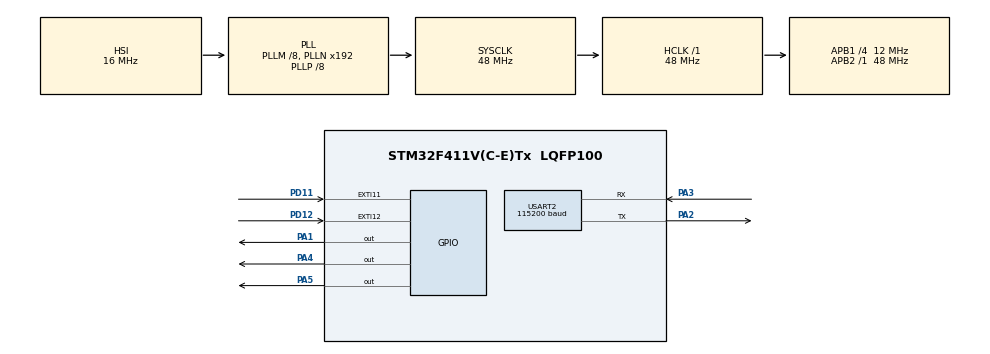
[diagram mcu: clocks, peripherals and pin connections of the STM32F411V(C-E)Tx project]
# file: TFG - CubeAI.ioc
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Mcu.Family=STM32F4
Mcu.Name=STM32F411V(C-E)Tx
Mcu.Package=LQFP100
NVIC.EXTI15_10_IRQn=true\:7\:0\:false\:false\:true\:true\:true\:false
NVIC.PriorityGroup=NVIC_PRIORITYGROUP_0
NVIC.TIM1_UP_TIM10_IRQn=true\:5\:0\:false\:false\:true\:true\:true\:false
NVIC.USART2_IRQn=true\:6\:0\:false\:false\:true\:true\:true\:false
PA1.Signal=GPIO_Output
PA2.Mode=Asynchronous
PA2.Signal=USART2_TX
PA3.Mode=Asynchronous
PA3.Signal=USART2_RX
PA4.Signal=GPIO_Output
PA5.Signal=GPIO_Output
PD11.Signal=GPXTI11
PD12.Signal=GPXTI12
ProjectManager.HeapSize=0x200
ProjectManager.StackSize=0x400
ProjectManager.TargetToolchain=STM32CubeIDE
RCC.48MHZClocksFreq_Value=48000000
RCC.AHBFreq_Value=48000000
RCC.APB1CLKDivider=RCC_HCLK_DIV4
RCC.APB1Freq_Value=12000000
RCC.APB1TimFreq_Value=24000000
RCC.APB2Freq_Value=48000000
RCC.APB2TimFreq_Value=48000000
RCC.CortexFreq_Value=48000000
RCC.HCLKFreq_Value=48000000
RCC.HSE_VALUE=8000000
RCC.HSI_VALUE=16000000
RCC.PLLI2SM=5
RCC.PLLI2SN=200
RCC.PLLM=8
RCC.PLLP=RCC_PLLP_DIV8
RCC.PLLQ=8
RCC.SYSCLKFreq_VALUE=48000000
RCC.SYSCLKSource=RCC_SYSCLKSOURCE_PLLCLK
RCC.VCOOutputFreq_Value=384000000
TIM1.Period=65535
TIM1.Prescaler=47
USART2.BaudRate=115200
USART2.VirtualMode=VM_ASYNC
board=STM32F411E-DISCO

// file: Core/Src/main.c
/* USER CODE BEGIN Header */
/**
  ******************************************************************************
  * @file           : main.c
  * @brief          : Main program body
  ******************************************************************************
  * @attention
  *
  * Copyright (c) 2026 STMicroelectronics.
  * All rights reserved.
  *
  * This software is licensed under terms that can be found in the LICENSE file
  * in the root directory of this software component.
  * If no LICENSE file comes with this software, it is provided AS-IS.
  *
  ******************************************************************************
  */
/* USER CODE END Header */
#include "main.h"
/* USER CODE BEGIN Includes */
#include <string.h>
#include "state_m.h"
#include "ai_bridge.h"
/* USER CODE END Includes */

TIM_HandleTypeDef htim1;
UART_HandleTypeDef huart2;

/* USER CODE BEGIN PV */
volatile uint32_t g_tim1_ovf_count = 0;
/* USER CODE END PV */

void SystemClock_Config(void);
static void MX_GPIO_Init(void);
/* USER CODE BEGIN PFP */
static void MX_TIM1_Init(void);
static void MX_USART2_UART_Init(void);
/* USER CODE END PFP */

int main(void)
{

  /* MCU Configuration--------------------------------------------------------*/

  /* Reset of all peripherals, Initializes the Flash interface and the Systick. */
  HAL_Init();

  /* Configure the system clock */
  SystemClock_Config();

  /* USER CODE BEGIN SysInit */
  AI_Init();
  /* USER CODE END SysInit */

  /* Initialize all configured peripherals */
  MX_GPIO_Init();
  MX_TIM1_Init();
  MX_USART2_UART_Init();
  /* USER CODE BEGIN 2 */
  StateMachine_Init();
  /* USER CODE END 2 */

  /* Infinite loop */
  while (1)
  {
    /* USER CODE BEGIN 3 */

    StateMachine_Run();

  }
  /* USER CODE END 3 */
}

void SystemClock_Config(void)
{
  RCC_OscInitTypeDef RCC_OscInitStruct = {0};
  RCC_ClkInitTypeDef RCC_ClkInitStruct = {0};

  /** Configure the main internal regulator output voltage
  */
  __HAL_RCC_PWR_CLK_ENABLE();
  __HAL_PWR_VOLTAGESCALING_CONFIG(PWR_REGULATOR_VOLTAGE_SCALE1);

  /** Initializes the RCC Oscillators according to the specified parameters
  * in the RCC_OscInitTypeDef structure.
  */
  RCC_OscInitStruct.OscillatorType = RCC_OSCILLATORTYPE_HSI;
  RCC_OscInitStruct.HSIState = RCC_HSI_ON;
  RCC_OscInitStruct.HSICalibrationValue = RCC_HSICALIBRATION_DEFAULT;
  RCC_OscInitStruct.PLL.PLLState = RCC_PLL_ON;
  RCC_OscInitStruct.PLL.PLLSource = RCC_PLLSOURCE_HSI;
  RCC_OscInitStruct.PLL.PLLM = 8;
  RCC_OscInitStruct.PLL.PLLN = 192;
  RCC_OscInitStruct.PLL.PLLP = RCC_PLLP_DIV8;
  RCC_OscInitStruct.PLL.PLLQ = 8;
  if (HAL_RCC_OscConfig(&RCC_OscInitStruct) != HAL_OK)
  {
    Error_Handler();
  }

  /** Initializes the CPU, AHB and APB buses clocks
  */
  RCC_ClkInitStruct.ClockType = RCC_CLOCKTYPE_HCLK|RCC_CLOCKTYPE_SYSCLK
                              |RCC_CLOCKTYPE_PCLK1|RCC_CLOCKTYPE_PCLK2;
  RCC_ClkInitStruct.SYSCLKSource = RCC_SYSCLKSOURCE_PLLCLK;
  RCC_ClkInitStruct.AHBCLKDivider = RCC_SYSCLK_DIV1;
  RCC_ClkInitStruct.APB1CLKDivider = RCC_HCLK_DIV4;
  RCC_ClkInitStruct.APB2CLKDivider = RCC_HCLK_DIV1;

  if (HAL_RCC_ClockConfig(&RCC_ClkInitStruct, FLASH_LATENCY_1) != HAL_OK)
  {
    Error_Handler();
  }
}

static void MX_GPIO_Init(void)
{
  GPIO_InitTypeDef GPIO_InitStruct = {0};

  /* GPIO Ports Clock Enable */
  __HAL_RCC_GPIOA_CLK_ENABLE();
  __HAL_RCC_GPIOD_CLK_ENABLE();

  /*Configure GPIO pins Output Level */
  HAL_GPIO_WritePin(GPIOA, LED_IDLE_Pin | LED_WAITING_Pin | LED_BUSY_Pin, GPIO_PIN_RESET);

  /*Configure GPIO pin : PD11 (BUTTON_MANUAL) */
  GPIO_InitStruct.Pin = BUTTON_MANUAL_Pin;
  GPIO_InitStruct.Mode = GPIO_MODE_IT_RISING;
  GPIO_InitStruct.Pull = GPIO_PULLDOWN;
  HAL_GPIO_Init(BUTTON_MANUAL_GPIO_Port, &GPIO_InitStruct);

  /*Configure GPIO pin : PD12 (BUTTON_AUTO) */
  GPIO_InitStruct.Pin = BUTTON_AUTO_Pin;
  GPIO_InitStruct.Mode = GPIO_MODE_IT_RISING;
  GPIO_InitStruct.Pull = GPIO_PULLDOWN;
  HAL_GPIO_Init(BUTTON_AUTO_GPIO_Port, &GPIO_InitStruct);

  /*Configure GPIO pins : PA1 (LED_IDLE), PA4 (LED_WAITING), PA5 (LED_BUSY) */
  GPIO_InitStruct.Pin = LED_IDLE_Pin | LED_WAITING_Pin | LED_BUSY_Pin;
  GPIO_InitStruct.Mode = GPIO_MODE_OUTPUT_PP;
  GPIO_InitStruct.Pull = GPIO_NOPULL;
  GPIO_InitStruct.Speed = GPIO_SPEED_FREQ_LOW;
  HAL_GPIO_Init(GPIOA, &GPIO_InitStruct);

  /* EXTI interrupt init */
  HAL_NVIC_SetPriority(BUTTONS_EXTI_IRQn, 7, 0);
  HAL_NVIC_EnableIRQ(BUTTONS_EXTI_IRQn);

}

static void MX_TIM1_Init(void)
{
  TIM_ClockConfigTypeDef sClockSourceConfig = {0};
  TIM_MasterConfigTypeDef sMasterConfig = {0};

  /* f_cnt = 48 MHz / (47 + 1) = 1 MHz -> resolución 1 us */
  htim1.Instance = TIM1;
  htim1.Init.Prescaler = 47;
  htim1.Init.CounterMode = TIM_COUNTERMODE_UP;
  htim1.Init.Period = 0xFFFF;
  htim1.Init.ClockDivision = TIM_CLOCKDIVISION_DIV1;
  htim1.Init.RepetitionCounter = 0;
  htim1.Init.AutoReloadPreload = TIM_AUTORELOAD_PRELOAD_DISABLE;
  if (HAL_TIM_Base_Init(&htim1) != HAL_OK)
  {
    Error_Handler();
  }

  sClockSourceConfig.ClockSource = TIM_CLOCKSOURCE_INTERNAL;
  if (HAL_TIM_ConfigClockSource(&htim1, &sClockSourceConfig) != HAL_OK)
  {
    Error_Handler();
  }

  sMasterConfig.MasterOutputTrigger = TIM_TRGO_RESET;
  sMasterConfig.MasterSlaveMode = TIM_MASTERSLAVEMODE_DISABLE;
  if (HAL_TIMEx_MasterConfigSynchronization(&htim1, &sMasterConfig) != HAL_OK)
  {
    Error_Handler();
  }
}

static void MX_USART2_UART_Init(void)
{
  huart2.Instance = USART2;
  huart2.Init.BaudRate = 115200;
  huart2.Init.WordLength = UART_WORDLENGTH_8B;
  huart2.Init.StopBits = UART_STOPBITS_1;
  huart2.Init.Parity = UART_PARITY_NONE;
  huart2.Init.Mode = UART_MODE_TX_RX;
  huart2.Init.HwFlowCtl = UART_HWCONTROL_NONE;
  huart2.Init.OverSampling = UART_OVERSAMPLING_16;
  if (HAL_UART_Init(&huart2) != HAL_OK)
  {
    Error_Handler();
  }
}

/* USER CODE BEGIN 4 */

/**
  * @brief  Lee el temporizador extendido de 1 us (g_tim1_ovf_count + contador
  *         de TIM1).
  * @retval Ticks de 1 us transcurridos desde el arranque del temporizador
  */
uint64_t Get_Timer1_Ticks_us(void)
{
  uint32_t ovf1, ovf2, cnt;

  do
  {
    ovf1 = g_tim1_ovf_count;
    cnt  = __HAL_TIM_GET_COUNTER(&htim1);
    ovf2 = g_tim1_ovf_count;
  } while (ovf1 != ovf2);

  return (((uint64_t)ovf1) << 16) | cnt;
}

/**
  * @brief  Envía una cadena terminada en '\0' por USART2 por interrupción.
  * @param  str Cadena a enviar
  * @retval None
  */
void UART2_SendString(const char *str)
{
  while (huart2.gState != HAL_UART_STATE_READY)
  {
  }

  HAL_UART_Transmit_IT(&huart2, (uint8_t *)str, (uint16_t)strlen(str));
}

/**
  * @brief  Callback HAL de desbordamiento de TIM1.
  * @param  htim Handle del temporizador
  * @retval None
  */
void HAL_TIM_PeriodElapsedCallback(TIM_HandleTypeDef *htim)
{
  if (htim->Instance == TIM1)
  {
    g_tim1_ovf_count++;
  }
}

/**
  * @brief  Callback HAL de fin de transmisión UART.
  * @param  huart Handle de la UART
  * @retval None
  */
void HAL_UART_TxCpltCallback(UART_HandleTypeDef *huart)
{
  if (huart->Instance == USART2)
  {
  }
}

/* USER CODE END 4 */

void Error_Handler(void)
{
  __disable_irq();
  while (1)
  {
  }
}
